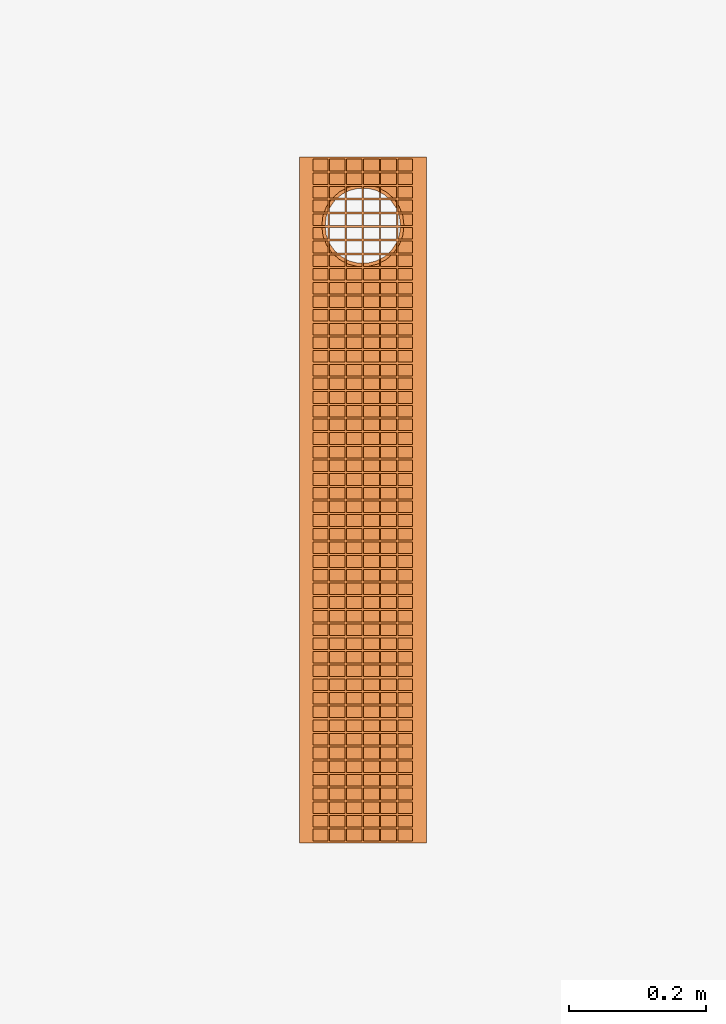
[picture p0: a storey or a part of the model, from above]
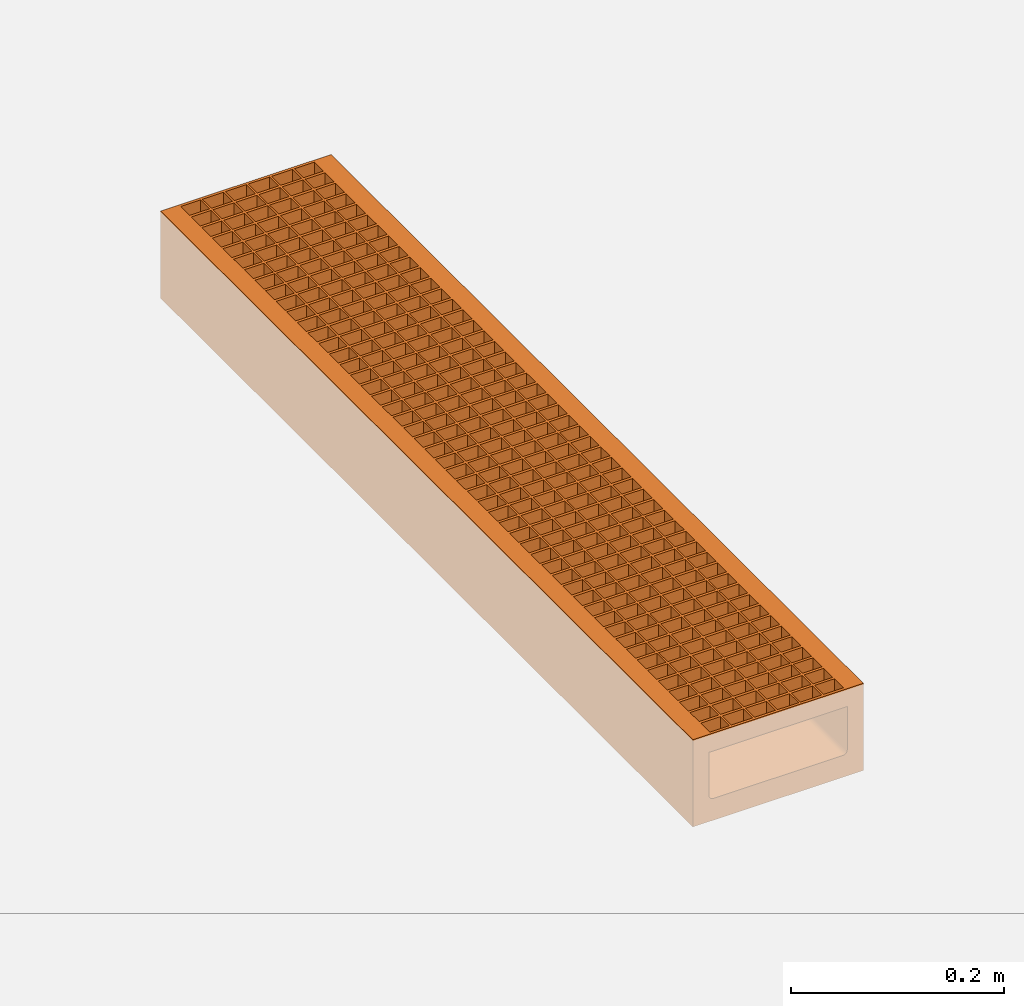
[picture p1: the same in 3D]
Properties of the parts of a building model (IFC2X3)

# File
Description: ViewDefinition [CoordinationView]
File name: 24157 - No 0100V Constant Depth Channel - 1000mm LG - Invert Depth 75mm.ifc
Time: 2013-10-17T16:58:30
Written by: Autodesk Revit 2013
Made in: 20120221_2030(x64)

# IfcProject, Project Number
LongName: Project Name; Phase: Project Status

# IfcSite, Default
RefLatitude: 42, 21, 30, 344238; RefLongitude: -71, -3, -35, -194702; RefElevation: 0 mm

# IfcBuilding
Pset_BuildingCommon - NumberOfStoreys: 1
Other - Project Address: ## Street City, State Zip; Project Issue Date: Issue Date; Project Number: Project Number; Project Status: Project Status; Client Name: Owner; Project Name: Project Name

# IfcBuildingStorey, Level 1
LongName: Level 1; Elevation: 0 mm
Constraints - Elevation Base: 0; Elevation: 0 mm
Graphics - Line Weight: 1; Color: 0; Line Pattern: Center; Symbol: M_Level Head - Circle: M_Level Head - Circle; Symbol at End 1 Default: no; Symbol at End 2 Default: yes
Dimensions - Computation Height: 0 mm
Identity Data - Name: Level 1; Building Story: yes; Structural: no

# IfcBuildingElementProxy: 24157 - No 0100V Constant Depth Channel - 1000mm LG - Invert Depth 75mm, Civil-Drainage-Channel-ACO-MultiDrain-M150DS-Channel-System-Custom_Final FL:24157 - No 0100V Constant Depth Channel - 1000mm LG - Invert Depth 75mm:24157 - No 0100V Constant Depth Channel - 1000mm LG - Invert Depth 75mm:199235
In: Level 1
Material: Plastic, Opaque Black, Vienite® Synthetic Resin Concrete
Other - Revision: 1; CreatedBy: www.aco.co.uk
Construction - 23159 - Universal Endcap (Female End): no; 13049 - Grating - Mesh - Stainless Steel - 500mm Long: no; 23159 - Universal Endcap (Male End): no; 13048 - Grating - Mesh - Stainless Steel - 1000mm Long: no; Grating_1000mm: yes; 24156_Shallow Depth Channel: no; Grating_500mm: no; Constant Depth Channel_1000: no; Constant Depth Channel_500: no; 24158_Sump Unit: no; 24157_Shallow Depth Channel with seal: yes
Dimensions - Volume: 7794490 mm3; Custom cut void length: 0 mm; EndCap Position: 1000 mm; Length: 1000 mm; FloorCut_Length: -1000 mm; InvDepth: 210 mm; FloorCut_HorPosition: 92.5 mm; FloorCut_Width: 185 mm; Depth: 310 mm; Mesh grating length: -1000 mm; EndCap_Height: 100 mm; FloorCut_Depth: 100 mm
Constraints - Level: Level: Level 1; Moves With Nearby Elements: no
Phasing - Phase Created: New Construction
Pset_BuildingElementProxyCommon - Reference: 24157 - No 0100V Constant Depth Channel - 1000mm LG - Invert Depth 75mm
Model Properties - Grating Product code 13049: Load Class C250 - Mesh Stainless Steel Grade 304 13049DL 500mm long - 23x17mm hole - Intake Area 115100mm²/m- 3.7kg; Grating Product code 13048: Load Class C250 - Mesh Stainless Steel Grade 304 13048DL 1000mm long - 23x17mm hole - Intake Area 115100mm²/m- 7.4kg; End Cap Product code 23159: No 306 Universal End Cap - 185mm wide x 310mm long - Spigot Ø160mm x 75mm long - Silver - Polypropylene - 0.3kg
Data - Concrete Surround Volume - Load Class D 400 - Concrete Pavement: 0.16m³/m; ACO Hydraulic Design Software: http://www.acodesign.co.uk; Product Weight: 15.9 Kg; Product Dimensions: 1000mm x 185mm x 100mm (LxWxH); Pre-formed Outlet Ø: 110mm; Channel C.S.A: 0.008m²; Concrete Surround Volume - Load Class B 125 - C 250 - Concrete Pavement: 0.10m³/m; Concrete Surround Volume - Load Class A 15 - Concrete Pavement: 0.06m³/m; Load Class: A 15 - D 400; Hydraulic Performance: http://www.aco.co.uk/download.php?id=173; Product Standard: BS EN 1433:2002, CE marked; Installation - Concrete Grade: Refer to brochure; Invert Depth: 75mm
Identity Data - Assembly Code: D2040; Assembly Description: Rain Water Drainage; Watermark 2: This file is water marked and users are prohibited to reproduce, adapt, distribute this information; Installation guidelines: http://www.aco.co.uk/download.php?id=173; Maintenance guidelines: http://www.aco.co.uk/download.php?id=173; Telephone: +44 (0)1462 816666; Cost: 0; Product Code: 24157; Address: ACO Business Park, Hitchin Road, Shefford, Bedfordshire, United Kingdom SG17 5TE; Watermarked By: www.aco.co.uk; OmniClass Title: Rainwater Removal; Product Page URL: http://www.aco.co.uk/product_detail.php?id=15; Manufacturer: ACO Technologies plc - ACO Water Management Division; Product brochure: http://www.aco.co.uk/download.php?id=173; Fax: +44 (0)1462 815895; OmniClass Number: 23.70.50.24; Model Description: Channel drainage system; URL: www.aco.co.uk; Watermark 1: This file is the property of ACO Technologies PLC; Model: ACO MultiDrain MD - M150DS; Type Comments: ACO MultiDrain M150DS 0100V Shallow Constant Depth Channel 1000mm Long; Watermarked With: BIM Manager Premium Suite; Price: POA - contact ACO; e-mail Technical: technical@aco.co.uk; e-mail Sales: customersupport@aco.co.uk
General - SerialNumber: 0; TagNumber: 0
Green Building Properties - Channel Recycled Material Content: 20% minimum; Channel Recyclable: Fully recyclable; Edge Rail Recycled Material Content: Between 40% - 90%; Edge Rail Recyclable: Fully recyclable
Materials and Finishes - Channel Material: Vienite® Synthetic Resin Concrete; Edge Rail Material: Stainless Steel Grade 304; Channel Colour: Brown; Edge Rail Colour: Self

# IfcOpeningElement: Opening, Civil-Drainage-Channel-ACO-MultiDrain-M150DS-Channel-System-Custom_Final FL:24157 - No 0100V Constant Depth Channel - 1000mm LG - Invert Depth 75mm:24157 - No 0100V Constant Depth Channel - 1000mm LG - Invert Depth 75mm:199235:1
In: Level 1
Other - Revision: 1; CreatedBy: www.aco.co.uk
Construction - 23159 - Universal Endcap (Female End): no; 13049 - Grating - Mesh - Stainless Steel - 500mm Long: no; 23159 - Universal Endcap (Male End): no; 13048 - Grating - Mesh - Stainless Steel - 1000mm Long: no; Grating_1000mm: yes; 24156_Shallow Depth Channel: no; Grating_500mm: no; Constant Depth Channel_1000: no; Constant Depth Channel_500: no; 24158_Sump Unit: no; 24157_Shallow Depth Channel with seal: yes
Dimensions - Volume: 7794490 mm3; Custom cut void length: 0 mm; EndCap Position: 1000 mm; Length: 1000 mm; FloorCut_Length: -1000 mm; InvDepth: 210 mm; FloorCut_HorPosition: 92.5 mm; FloorCut_Width: 185 mm; Depth: 310 mm; Mesh grating length: -1000 mm; EndCap_Height: 100 mm; FloorCut_Depth: 100 mm
Constraints - Level: Level: Level 1; Moves With Nearby Elements: no
Phasing - Phase Created: New Construction
Model Properties - Grating Product code 13049: Load Class C250 - Mesh Stainless Steel Grade 304 13049DL 500mm long - 23x17mm hole - Intake Area 115100mm²/m- 3.7kg; Grating Product code 13048: Load Class C250 - Mesh Stainless Steel Grade 304 13048DL 1000mm long - 23x17mm hole - Intake Area 115100mm²/m- 7.4kg; End Cap Product code 23159: No 306 Universal End Cap - 185mm wide x 310mm long - Spigot Ø160mm x 75mm long - Silver - Polypropylene - 0.3kg
Data - Concrete Surround Volume - Load Class D 400 - Concrete Pavement: 0.16m³/m; ACO Hydraulic Design Software: http://www.acodesign.co.uk; Product Weight: 15.9 Kg; Product Dimensions: 1000mm x 185mm x 100mm (LxWxH); Pre-formed Outlet Ø: 110mm; Channel C.S.A: 0.008m²; Concrete Surround Volume - Load Class B 125 - C 250 - Concrete Pavement: 0.10m³/m; Concrete Surround Volume - Load Class A 15 - Concrete Pavement: 0.06m³/m; Load Class: A 15 - D 400; Hydraulic Performance: http://www.aco.co.uk/download.php?id=173; Product Standard: BS EN 1433:2002, CE marked; Installation - Concrete Grade: Refer to brochure; Invert Depth: 75mm
Identity Data - Assembly Code: D2040; Assembly Description: Rain Water Drainage; Watermark 2: This file is water marked and users are prohibited to reproduce, adapt, distribute this information; Installation guidelines: http://www.aco.co.uk/download.php?id=173; Maintenance guidelines: http://www.aco.co.uk/download.php?id=173; Telephone: +44 (0)1462 816666; Cost: 0; Product Code: 24157; Address: ACO Business Park, Hitchin Road, Shefford, Bedfordshire, United Kingdom SG17 5TE; Watermarked By: www.aco.co.uk; OmniClass Title: Rainwater Removal; Product Page URL: http://www.aco.co.uk/product_detail.php?id=15; Manufacturer: ACO Technologies plc - ACO Water Management Division; Product brochure: http://www.aco.co.uk/download.php?id=173; Fax: +44 (0)1462 815895; OmniClass Number: 23.70.50.24; Model Description: Channel drainage system; URL: www.aco.co.uk; Watermark 1: This file is the property of ACO Technologies PLC; Model: ACO MultiDrain MD - M150DS; Type Comments: ACO MultiDrain M150DS 0100V Shallow Constant Depth Channel 1000mm Long; Watermarked With: BIM Manager Premium Suite; Price: POA - contact ACO; e-mail Technical: technical@aco.co.uk; e-mail Sales: customersupport@aco.co.uk
General - SerialNumber: 0; TagNumber: 0
Green Building Properties - Channel Recycled Material Content: 20% minimum; Channel Recyclable: Fully recyclable; Edge Rail Recycled Material Content: Between 40% - 90%; Edge Rail Recyclable: Fully recyclable
Materials and Finishes - Channel Material: Vienite® Synthetic Resin Concrete; Edge Rail Material: Stainless Steel Grade 304; Channel Colour: Brown; Edge Rail Colour: Self

# IfcOpeningElement: Recess
In: Level 1
Dimensions - Perimeter: 20000 mm; Thickness: 400 mm; Volume: 9981500000 mm3; Area: 25000000 mm2
Constraints - Height Offset From Level: 0 mm; Room Bounding: yes; Related to Mass: no; Level: Level: Level 1
Structural - Enable Analytical Model: no; Structural: no
Phasing - Phase Created: New Construction
Analytical Properties - Absorptance: 0.1; Roughness: 1
Construction - Default Thickness: 400 mm; Function: 0
Graphics - Coarse Scale Fill Color: 0

# IfcSlab: Floor:Generic Floor - 400mm, Floor:Generic Floor - 400mm:193825
In: Level 1
PredefinedType: FLOOR; Material: Default Roof 400 mm
Dimensions - Perimeter: 20000 mm; Thickness: 400 mm; Volume: 9981500000 mm3; Area: 25000000 mm2
Constraints - Height Offset From Level: 0 mm; Room Bounding: yes; Related to Mass: no; Level: Level: Level 1
Structural - Enable Analytical Model: no; Structural: no
Phasing - Phase Created: New Construction
Pset_SlabCommon - Reference: Generic Floor - 400mm; IsExternal: no; LoadBearing: yes
Analytical Properties - Absorptance: 0.1; Roughness: 1
Construction - Default Thickness: 400 mm; Function: 0
Graphics - Coarse Scale Fill Color: 0
